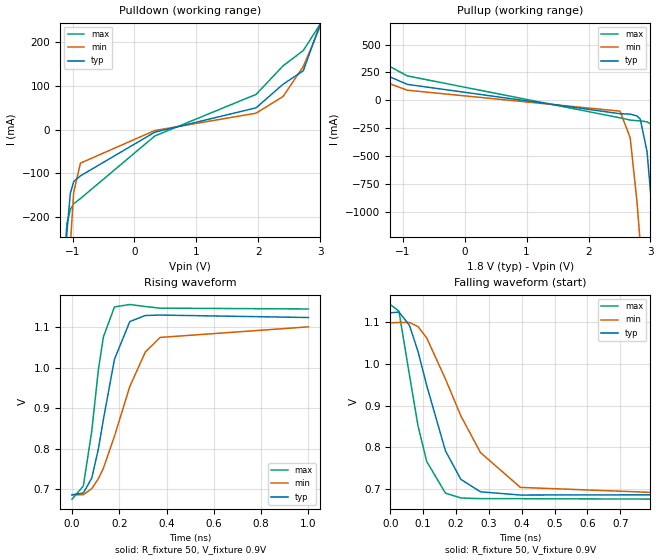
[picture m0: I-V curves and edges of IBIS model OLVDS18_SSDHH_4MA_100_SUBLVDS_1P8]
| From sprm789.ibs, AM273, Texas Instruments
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|   Model Cell OLVDS18_SSDHH_4MA_100_SUBLVDS_1P8
|OLVDS18_SSDHH_4MA_100_SUBLVDS_1P8
[Model]   OLVDS18_SSDHH_4MA_100_SUBLVDS_1P8
Model_type   Output
Polarity   Non-Inverting
Cref =  15.0001pF
Rref =  101.0000M
Vref =  0V
Vmeas =  1.08
C_comp   1.5p   1.5p   1.5p
[Temperature Range]   25   125   -40
[Voltage Range]   1.8   1.62   1.98
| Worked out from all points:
|   slope of the pulldown table from 0 to 0.27 V, typ, clamps not added: 14.5 ohm
|   slope of the pullup table from 0 to 0.27 V, typ, clamps not added: 11 ohm
|   rising waveform, R_fixture 50, V_fixture 0.9V: 20-80 % time 82.8ps typ, 145ps min, 56.8ps max; typ from 0.687 V to 1.12 V
|   falling waveform, R_fixture 50, V_fixture 0.9V: 20-80 % time 94.7ps typ, 152ps min, 65.6ps max; typ from 1.12 V to 0.686 V
| Nom Voltages:
|   BIAS1=1.2, BIAS2=1.2, VDD=1.1, VDDS=1.8, BUS_BIAS3=0, BUS_VSSS=0,
|   ESD_BIASFET=0, VSS=0
| Min Voltages:
|   BIAS1=1.2, BIAS2=1.2, VDD=0.99, VDDS=1.62, BUS_BIAS3=0, BUS_VSSS=0,
|   ESD_BIASFET=0, VSS=0
| Max Voltages:
|   BIAS1=1.2, BIAS2=1.2, VDD=1.21, VDDS=1.98, BUS_BIAS3=0, BUS_VSSS=0,
|   ESD_BIASFET=0, VSS=0
[Pulldown]
|   voltage   I(typ)   I(min)   I(max)
-1.8V     -5.997A    -6.31A     -5.865A
-1.145V   -444.7mA   -793.1mA   -323.8mA
-1.091V   -235mA     -485.1mA   -214.4mA
-1.036V   -145.6mA   -265.1mA   -182.9mA
-981.8mV  -118.4mA   -143.7mA   -169.4mA
-872.7mV  -105.5mA   -76.4mA    -157.4mA
327.3mV   -5.638mA   -1.825mA   -14.39mA
1.964V    50.15mA    37.92mA    80.87mA
2.4V      104.1mA    76.09mA    146.2mA
2.727V    135mA      144.8mA    181.3mA
3.055V    264.2mA    254.9mA    254mA
3.6V      552.6mA    862.1mA    610.6mA
[Pullup]
|   voltage   I(typ)   I(min)   I(max)
-1.8V     475.7mA    399.1mA    649.8mA
-1.309V   234.4mA    168.8mA    333.5mA
-927.3mV  142.3mA    89.88mA    218.4mA
2.509V    -121.3mA   -98.38mA   -158.3mA
2.673V    -124.8mA   -336.6mA   -178.3mA
2.782V    -141.4mA   -907.8mA   -184mA
2.836V    -170.1mA   -1.289A    -184.9mA
2.945V    -461.1mA   -2.15A     -194.8mA
3.055V    -1.17A     -3.083A    -228.3mA
3.164V    -2.06A     -4.046A    -505.6mA
3.273V    -3.022A    -5.011A    -1.263A
3.6V      -6.001A    -7.906A    -4.195A
[Ramp]
| variable   typ   min   max
dV/dt_f 0.18191049/97.259722p 0.15593189/0.14627382n 0.22158214/81.912241p
dV/dt_r 0.26008288/85.557834p 0.22969898/0.14240626n  0.2949732/60.138567p
R_load = 50
[Rising Waveform]
R_fixture = 50
V_fixture = 0.9V
V_fixture_min = 0.9V
V_fixture_max = 0.9V
|   time   V(typ)   V(min)   V(max)
0s        687mV      686.6mV    675.7mV
48.15ps   691.4mV    687.1mV    708.8mV
83.61ps   727.8mV    702.1mV    843.5mV
111.7ps   799.7mV    726.4mV    994.4mV
132.8ps   872mV      752.2mV    1.075V
179.6ps   1.02V      830.7mV    1.149V
244.6ps   1.113V     953.4mV    1.155V
310.2ps   1.128V     1.038V     1.15V
372.8ps   1.129V     1.074V     1.146V
1ns       1.123V     1.1V       1.144V
[Falling Waveform]
R_fixture = 50
V_fixture = 0.9V
V_fixture_min = 0.9V
V_fixture_max = 0.9V
|   time   V(typ)   V(min)   V(max)
0s        1.122V     1.098V     1.142V
26.23ps   1.124V     1.099V     1.126V
58.19ps   1.092V     1.099V     972.8mV
84.4ps    1.029V     1.089V     850.9mV
110.7ps   948.3mV    1.062V     766mV
167.9ps   791.3mV    963.4mV    690.1mV
214.7ps   723.1mV    875.2mV    678.6mV
274.6ps   693.3mV    787.2mV    676.9mV
396ps     685.6mV    703.9mV    676.9mV
1ns       686.4mV    685.7mV    675.3mV
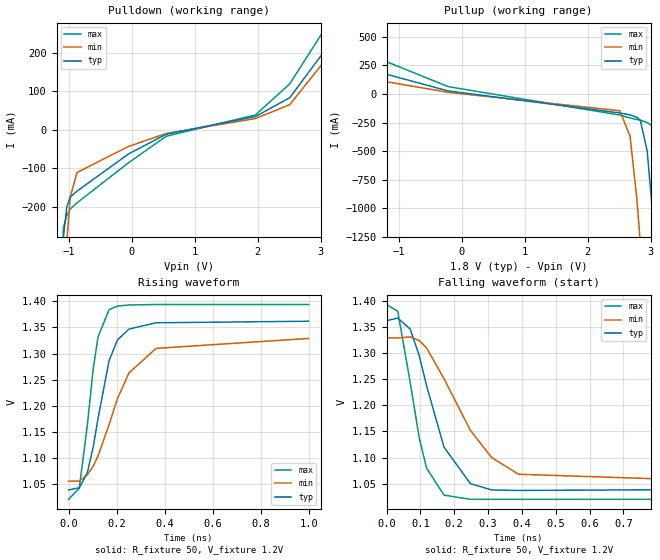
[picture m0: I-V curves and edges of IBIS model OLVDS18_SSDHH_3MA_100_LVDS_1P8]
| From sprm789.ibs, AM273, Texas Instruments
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|   Model Cell OLVDS18_SSDHH_3MA_100_LVDS_1P8
|OLVDS18_SSDHH_3MA_100_LVDS_1P8
[Model]   OLVDS18_SSDHH_3MA_100_LVDS_1P8
Model_type   Output
Polarity   Non-Inverting
Cref =  15.0001pF
Rref =  101.0000M
Vref =  0V
Vmeas =  1.08
C_comp   1.5p   1.5p   1.5p
[Temperature Range]   25   125   -40
[Voltage Range]   1.8   1.62   1.98
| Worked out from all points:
|   slope of the pulldown table from 0 to 0.27 V, typ, clamps not added: 9.82 ohm
|   slope of the pullup table from 0 to 0.27 V, typ, clamps not added: 25.2 ohm
|   rising waveform, R_fixture 50, V_fixture 1.2V: 20-80 % time 80.9ps typ, 140ps min, 54.5ps max; typ from 1.04 V to 1.36 V
|   falling waveform, R_fixture 50, V_fixture 1.2V: 20-80 % time 85.4ps typ, 143ps min, 59ps max; typ from 1.36 V to 1.04 V
| Nom Voltages:
|   BIAS1=1.2, BIAS2=1.2, VDD=1.1, VDDS=1.8, BUS_BIAS3=0, BUS_VSSS=0,
|   ESD_BIASFET=0, VSS=0
| Min Voltages:
|   BIAS1=1.2, BIAS2=1.2, VDD=0.99, VDDS=1.62, BUS_BIAS3=0, BUS_VSSS=0,
|   ESD_BIASFET=0, VSS=0
| Max Voltages:
|   BIAS1=1.2, BIAS2=1.2, VDD=1.21, VDDS=1.98, BUS_BIAS3=0, BUS_VSSS=0,
|   ESD_BIASFET=0, VSS=0
[Pulldown]
|   voltage   I(typ)   I(min)   I(max)
-1.8V     -6.003A    -6.315A    -5.869A
-1.091V   -280.6mA   -504mA     -254.8mA
-1.036V   -200.4mA   -290.6mA   -222.5mA
-981.8mV  -175.1mA   -175mA     -206.4mA
-872.7mV  -159.8mA   -111.1mA   -190.1mA
-54.55mV  -62.93mA   -43.42mA   -85.81mA
545.5mV   -11.5mA    -9.788mA   -16.87mA
1.964V    34.37mA    29.24mA    38.61mA
2.509V    83.4mA     65.25mA    119.5mA
3.164V    227.4mA    199.7mA    287.4mA
3.382V    295.2mA    298.5mA    403.3mA
3.6V      374.9mA    801.1mA    536.2mA
[Pullup]
|   voltage   I(typ)   I(min)   I(max)
-1.8V     321.7mA    319.1mA    577mA
-1.255V   180.9mA    112.4mA    294.8mA
-218.2mV  26.9mA     14.83mA    64.67mA
2.509V    -165.6mA   -146.3mA   -184.2mA
2.673V    -182.3mA   -368.3mA   -209.3mA
2.782V    -203.3mA   -924.6mA   -223.2mA
2.836V    -230.3mA   -1.302A    -228.8mA
2.945V    -496.6mA   -2.158A    -249.3mA
3.055V    -1.186A    -3.089A    -290.7mA
3.164V    -2.07A     -4.052A    -542.6mA
3.273V    -3.029A    -5.017A    -1.279A
3.6V      -6.007A    -7.911A    -4.201A
[Ramp]
| variable   typ   min   max
dV/dt_f 0.19168188/0.10159416n 0.15994001/0.15868861n 0.22678237/73.911952p
dV/dt_r 0.24315086/0.10135387n 0.19243998/0.15684725n 0.28731072/71.710216p
R_load = 50
[Rising Waveform]
R_fixture = 50
V_fixture = 1.2V
V_fixture_min = 1.2V
V_fixture_max = 1.2V
|   time   V(typ)   V(min)   V(max)
0s        1.039V     1.056V     1.021V
44.78ps   1.043V     1.056V     1.042V
78.34ps   1.072V     1.068V     1.163V
103.1ps   1.122V     1.085V     1.272V
123ps     1.176V     1.104V     1.332V
168.7ps   1.286V     1.164V     1.384V
203.3ps   1.326V     1.213V     1.391V
251.7ps   1.347V     1.263V     1.393V
365ps     1.359V     1.31V      1.394V
1ns       1.362V     1.329V     1.394V
[Falling Waveform]
R_fixture = 50
V_fixture = 1.2V
V_fixture_min = 1.2V
V_fixture_max = 1.2V
|   time   V(typ)   V(min)   V(max)
0s        1.362V     1.329V     1.393V
33.18ps   1.367V     1.329V     1.38V
69.98ps   1.346V     1.331V     1.244V
96.57ps   1.295V     1.324V     1.138V
118.2ps   1.238V     1.31V      1.08V
169.8ps   1.12V      1.251V     1.028V
248ps     1.05V      1.152V     1.02V
310.7ps   1.038V     1.1V       1.02V
390.3ps   1.037V     1.068V     1.02V
1ns       1.039V     1.055V     1.02V
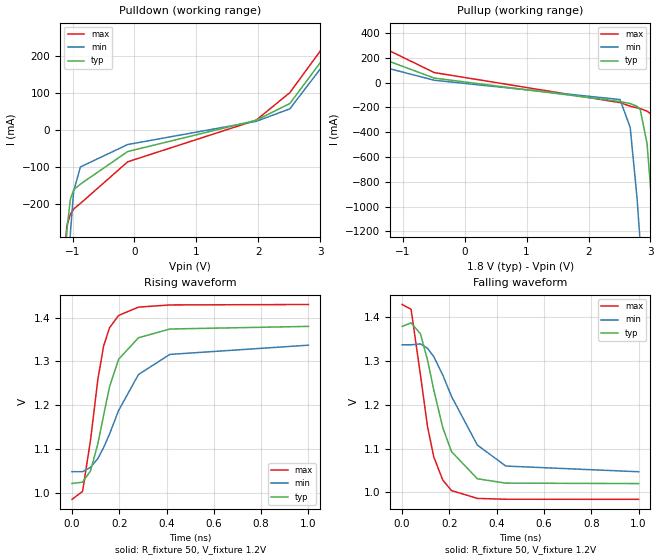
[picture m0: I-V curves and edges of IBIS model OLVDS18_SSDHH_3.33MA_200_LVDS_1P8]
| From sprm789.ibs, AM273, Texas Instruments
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|   Model Cell OLVDS18_SSDHH_3.33MA_200_LVDS_1P8
|OLVDS18_SSDHH_3.33MA_200_LVDS_1P8
[Model]   OLVDS18_SSDHH_3.33MA_200_LVDS_1P8
Model_type   Output
Polarity   Non-Inverting
Cref =  15.0001pF
Rref =  101.0000M
Vref =  0V
Vmeas =  1.08
C_comp   1.5p   1.5p   1.5p
[Temperature Range]   25   125   -40
[Voltage Range]   1.8   1.62   1.98
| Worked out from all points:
|   slope of the pulldown table from 0 to 0.27 V, typ, clamps not added: 10.7 ohm
|   slope of the pullup table from 0 to 0.27 V, typ, clamps not added: 34.5 ohm
|   rising waveform, R_fixture 50, V_fixture 1.2V: 20-80 % time 98.8ps typ, 160ps min, 68.5ps max; typ from 1.02 V to 1.38 V
|   falling waveform, R_fixture 50, V_fixture 1.2V: 20-80 % time 104ps typ, 160ps min, 76.9ps max; typ from 1.38 V to 1.02 V
| Nom Voltages:
|   BIAS1=1.2, BIAS2=1.2, VDD=1.1, VDDS=1.8, BUS_BIAS3=0, BUS_VSSS=0,
|   ESD_BIASFET=0, VSS=0
| Min Voltages:
|   BIAS1=1.2, BIAS2=1.2, VDD=0.99, VDDS=1.62, BUS_BIAS3=0, BUS_VSSS=0,
|   ESD_BIASFET=0, VSS=0
| Max Voltages:
|   BIAS1=1.2, BIAS2=1.2, VDD=1.21, VDDS=1.98, BUS_BIAS3=0, BUS_VSSS=0,
|   ESD_BIASFET=0, VSS=0
[Pulldown]
|   voltage   I(typ)   I(min)   I(max)
-1.8V     -6.002A    -6.313A    -5.869A
-1.145V   -469.1mA   -802.4mA   -357.8mA
-1.091V   -270.3mA   -497.9mA   -258.3mA
-1.036V   -188mA     -282.5mA   -228.2mA
-981.8mV  -162mA     -165.2mA   -213.7mA
-872.7mV  -146.6mA   -100.3mA   -198.7mA
-109.1mV  -58.72mA   -39.87mA   -86.43mA
1.964V    25.56mA    22.55mA    25.7mA
2.509V    70.6mA     56.36mA    100.1mA
3.273V    242.3mA    223.4mA    274.5mA
3.382V    278.4mA    290.7mA    313.4mA
3.6V      357.4mA    796.4mA    404.5mA
[Pullup]
|   voltage   I(typ)   I(min)   I(max)
-1.8V     309mA      313.3mA    437.4mA
-1.418V   209.6mA    139.6mA    307.4mA
-490.9mV  37.11mA    19.76mA    81.69mA
2.509V    -151.8mA   -135.8mA   -160.9mA
2.673V    -168.5mA   -360.8mA   -189.2mA
2.782V    -189.5mA   -920.5mA   -203.3mA
2.836V    -217.2mA   -1.299A    -209mA
2.945V    -488.9mA   -2.156A    -229.7mA
3.055V    -1.183A    -3.087A    -271.6mA
3.164V    -2.068A    -4.05A     -532mA
3.273V    -3.027A    -5.015A    -1.274A
3.6V      -6.006A    -7.91A     -4.2A
[Ramp]
| variable   typ   min   max
dV/dt_f 0.19787594/0.11739562n 0.15891786/0.16781205n 0.25058059/94.168038p
dV/dt_r 0.26663218/0.11549698n 0.19998742/0.17131782n 0.34035729/85.018329p
R_load = 50
[Rising Waveform]
R_fixture = 50
V_fixture = 1.2V
V_fixture_min = 1.2V
V_fixture_max = 1.2V
|   time   V(typ)   V(min)   V(max)
0s        1.021V     1.048V     984.8mV
44.88ps   1.024V     1.048V     1.003V
78.69ps   1.05V      1.058V     1.121V
109.5ps   1.112V     1.078V     1.259V
133.8ps   1.177V     1.103V     1.335V
158.9ps   1.242V     1.134V     1.377V
197.3ps   1.305V     1.188V     1.405V
281.3ps   1.354V     1.27V      1.424V
414ps     1.374V     1.316V     1.429V
1ns       1.38V      1.337V     1.43V
[Falling Waveform]
R_fixture = 50
V_fixture = 1.2V
V_fixture_min = 1.2V
V_fixture_max = 1.2V
|   time   V(typ)   V(min)   V(max)
0s        1.379V     1.337V     1.429V
37.76ps   1.387V     1.337V     1.418V
77.38ps   1.362V     1.339V     1.268V
107.3ps   1.302V     1.329V     1.15V
133.7ps   1.234V     1.31V      1.081V
171.6ps   1.148V     1.268V     1.028V
208.7ps   1.093V     1.219V     1.004V
317.9ps   1.031V     1.108V     986.1mV
438.2ps   1.021V     1.06V      984.2mV
1ns       1.02V      1.047V     984mV
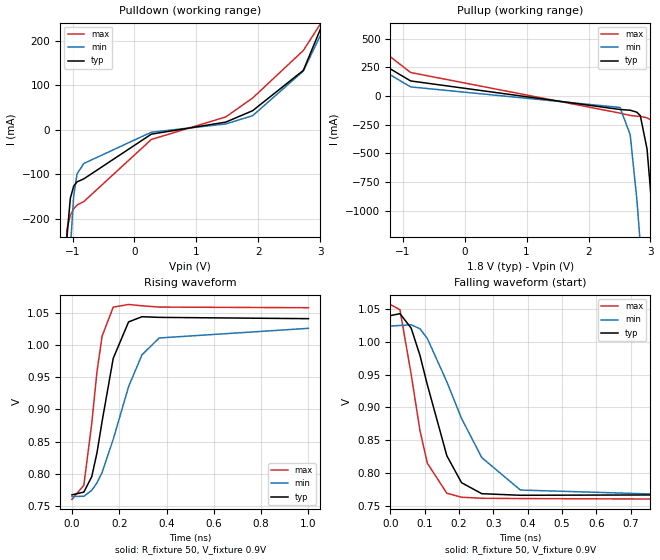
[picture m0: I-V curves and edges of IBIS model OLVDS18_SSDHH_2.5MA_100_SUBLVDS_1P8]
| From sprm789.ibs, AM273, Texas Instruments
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|   Model Cell OLVDS18_SSDHH_2.5MA_100_SUBLVDS_1P8
|OLVDS18_SSDHH_2.5MA_100_SUBLVDS_1P8
[Model]   OLVDS18_SSDHH_2.5MA_100_SUBLVDS_1P8
Model_type   Output
Polarity   Non-Inverting
Cref =  15.0001pF
Rref =  101.0000M
Vref =  0V
Vmeas =  1.08
C_comp   1.5p   1.5p   1.5p
[Temperature Range]   25   125   -40
[Voltage Range]   1.8   1.62   1.98
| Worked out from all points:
|   slope of the pulldown table from 0 to 0.27 V, typ, clamps not added: 16 ohm
|   slope of the pullup table from 0 to 0.27 V, typ, clamps not added: 13 ohm
|   rising waveform, R_fixture 50, V_fixture 0.9V: 20-80 % time 78.5ps typ, 136ps min, 53.2ps max; typ from 0.767 V to 1.04 V
|   falling waveform, R_fixture 50, V_fixture 0.9V: 20-80 % time 85.2ps typ, 137ps min, 58.3ps max; typ from 1.04 V to 0.766 V
| Nom Voltages:
|   BIAS1=1.2, BIAS2=1.2, VDD=1.1, VDDS=1.8, BUS_BIAS3=0, BUS_VSSS=0,
|   ESD_BIASFET=0, VSS=0
| Min Voltages:
|   BIAS1=1.2, BIAS2=1.2, VDD=0.99, VDDS=1.62, BUS_BIAS3=0, BUS_VSSS=0,
|   ESD_BIASFET=0, VSS=0
| Max Voltages:
|   BIAS1=1.2, BIAS2=1.2, VDD=1.21, VDDS=1.98, BUS_BIAS3=0, BUS_VSSS=0,
|   ESD_BIASFET=0, VSS=0
[Pulldown]
|   voltage   I(typ)   I(min)   I(max)
-1.8V     -5.998A    -6.311A    -5.866A
-1.091V   -242.4mA   -488.3mA   -223.9mA
-1.036V   -154.3mA   -269.5mA   -192.3mA
-981.8mV  -126.9mA   -149.1mA   -178mA
-927.3mV  -117.1mA   -99.25mA   -169.2mA
-818.2mV  -110.4mA   -75.84mA   -161.5mA
272.7mV   -9.894mA   -5.523mA   -21.84mA
1.473V    17.07mA    12.97mA    28.68mA
1.909V    42.86mA    31.63mA    71.37mA
2.727V    133.4mA    131.9mA    178.1mA
3.055V    243.6mA    227.2mA    249.1mA
3.6V      493.3mA    842.2mA    552.5mA
[Pullup]
|   voltage   I(typ)   I(min)   I(max)
-1.8V     427.9mA    374.4mA    591.9mA
-872.7mV  130.7mA    78.78mA    204.1mA
2.509V    -118mA     -100.3mA   -149.8mA
2.673V    -124.5mA   -338mA     -170.3mA
2.782V    -142.2mA   -908.5mA   -176.7mA
2.836V    -171.2mA   -1.29A     -178.4mA
2.945V    -461.9mA   -2.15A     -190.4mA
3.055V    -1.17A     -3.083A    -226.3mA
3.109V    -1.602A    -3.564A    -298.8mA
3.164V    -2.06A     -4.047A    -505.4mA
3.273V    -3.022A    -5.011A    -1.263A
3.6V      -6.001A    -7.906A    -4.195A
[Ramp]
| variable   typ   min   max
dV/dt_f  0.1007977/94.40248p  91.498081m/0.14147129n 0.12834191/97.17861p
dV/dt_r 0.13244323/84.246346p 0.10726775/0.137929n  0.16642625/56.717463p
R_load = 50
[Rising Waveform]
R_fixture = 50
V_fixture = 0.9V
V_fixture_min = 0.9V
V_fixture_max = 0.9V
|   time   V(typ)   V(min)   V(max)
0s        767.4mV    764.8mV    760.4mV
50.16ps   771.6mV    765.1mV    782.2mV
83.61ps   795.6mV    774.4mV    878.2mV
105.8ps   832.7mV    786mV      958.8mV
127.5ps   881.7mV    802.2mV    1.014V
174.5ps   979.4mV    853.6mV    1.059V
239.4ps   1.036V     935.4mV    1.063V
296.2ps   1.044V     984.9mV    1.061V
368.8ps   1.043V     1.011V     1.059V
1ns       1.041V     1.026V     1.058V
[Falling Waveform]
R_fixture = 50
V_fixture = 0.9V
V_fixture_min = 0.9V
V_fixture_max = 0.9V
|   time   V(typ)   V(min)   V(max)
0s        1.04V      1.024V     1.057V
28.04ps   1.043V     1.025V     1.049V
60.65ps   1.021V     1.026V     950.5mV
86.21ps   979.5mV    1.02V      864.9mV
107.9ps   934.3mV    1.005V     814.6mV
164.7ps   826mV      938.9mV    768.8mV
207.5ps   784.9mV    883mV      762.7mV
266.5ps   768.1mV    823.2mV    761.1mV
379ps     765.7mV    773.7mV    760.7mV
1ns       766.5mV    763.9mV    759.5mV
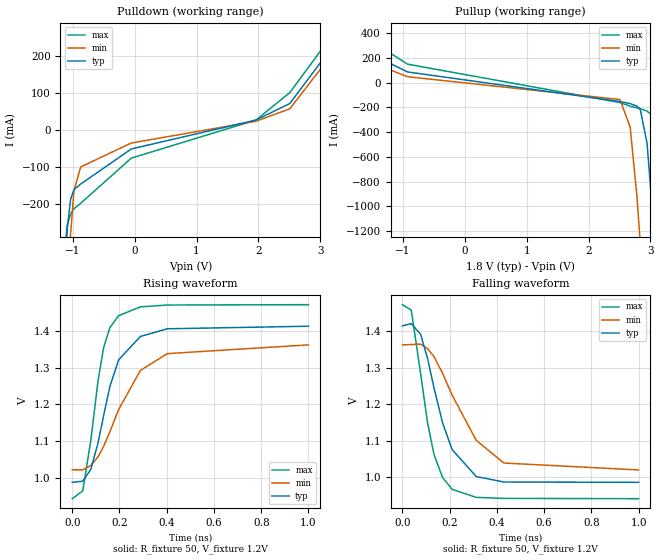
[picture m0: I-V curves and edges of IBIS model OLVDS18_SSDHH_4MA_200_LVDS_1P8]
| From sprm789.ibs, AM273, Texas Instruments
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|   Model Cell OLVDS18_SSDHH_4MA_200_LVDS_1P8
|OLVDS18_SSDHH_4MA_200_LVDS_1P8
[Model]   OLVDS18_SSDHH_4MA_200_LVDS_1P8
Model_type   Output
Polarity   Non-Inverting
Cref =  15.0001pF
Rref =  101.0000M
Vref =  0V
Vmeas =  1.08
C_comp   1.5p   1.5p   1.5p
[Temperature Range]   25   125   -40
[Voltage Range]   1.8   1.62   1.98
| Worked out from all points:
|   slope of the pulldown table from 0 to 0.27 V, typ, clamps not added: 10.4 ohm
|   slope of the pullup table from 0 to 0.27 V, typ, clamps not added: 30.6 ohm
|   rising waveform, R_fixture 50, V_fixture 1.2V: 20-80 % time 99.5ps typ, 155ps min, 69ps max; typ from 0.987 V to 1.41 V
|   falling waveform, R_fixture 50, V_fixture 1.2V: 20-80 % time 108ps typ, 166ps min, 79.6ps max; typ from 1.41 V to 0.986 V
| Nom Voltages:
|   BIAS1=1.2, BIAS2=1.2, VDD=1.1, VDDS=1.8, BUS_BIAS3=0, BUS_VSSS=0,
|   ESD_BIASFET=0, VSS=0
| Min Voltages:
|   BIAS1=1.2, BIAS2=1.2, VDD=0.99, VDDS=1.62, BUS_BIAS3=0, BUS_VSSS=0,
|   ESD_BIASFET=0, VSS=0
| Max Voltages:
|   BIAS1=1.2, BIAS2=1.2, VDD=1.21, VDDS=1.98, BUS_BIAS3=0, BUS_VSSS=0,
|   ESD_BIASFET=0, VSS=0
[Pulldown]
|   voltage   I(typ)   I(min)   I(max)
-1.8V     -6.002A    -6.313A    -5.869A
-1.145V   -469.2mA   -802.4mA   -358.1mA
-1.091V   -270.5mA   -498mA     -258.7mA
-1.036V   -188.3mA   -282.6mA   -228.6mA
-981.8mV  -162.4mA   -165.4mA   -214.2mA
-872.7mV  -147.1mA   -100.6mA   -199.3mA
-54.55mV  -51.85mA   -35.77mA   -76.77mA
1.964V    26.68mA    23.43mA    26.84mA
2.509V    71.64mA    57.21mA    101.3mA
3.273V    242.7mA    223.5mA    275.5mA
3.382V    278.8mA    290.7mA    314.4mA
3.6V      357.6mA    796.2mA    405.4mA
[Pullup]
|   voltage   I(typ)   I(min)   I(max)
-1.8V     306.5mA    311.8mA    434.7mA
-1.582V   248.4mA    176.8mA    360.7mA
-927.3mV  87.71mA    48.97mA    150.6mA
2.509V    -151.7mA   -135.7mA   -160.7mA
2.673V    -168.4mA   -360.7mA   -189.1mA
2.782V    -189.4mA   -920.4mA   -203.2mA
2.836V    -217.1mA   -1.299A    -209mA
2.945V    -488.8mA   -2.156A    -229.6mA
3.055V    -1.183A    -3.087A    -271.6mA
3.164V    -2.068A    -4.05A     -532mA
3.273V    -3.027A    -5.015A    -1.274A
3.6V      -6.006A    -7.91A     -4.2A
[Ramp]
| variable   typ   min   max
dV/dt_f 0.23525211/0.12064186n 0.18932691/0.17314391n 0.29708818/96.099177p
dV/dt_r 0.30711866/0.1083655n  0.2305142/0.16020396n 0.39283537/80.525444p
R_load = 50
[Rising Waveform]
R_fixture = 50
V_fixture = 1.2V
V_fixture_min = 1.2V
V_fixture_max = 1.2V
|   time   V(typ)   V(min)   V(max)
0s        986.9mV    1.021V     942.1mV
44.53ps   990mV      1.021V     963.5mV
78.34ps   1.022V     1.033V     1.101V
109.4ps   1.095V     1.057V     1.266V
132.7ps   1.169V     1.085V     1.355V
159.2ps   1.249V     1.125V     1.41V
196.4ps   1.322V     1.186V     1.443V
288.4ps   1.386V     1.293V     1.467V
402.3ps   1.407V     1.339V     1.472V
1ns       1.414V     1.363V     1.473V
[Falling Waveform]
R_fixture = 50
V_fixture = 1.2V
V_fixture_min = 1.2V
V_fixture_max = 1.2V
|   time   V(typ)   V(min)   V(max)
0s        1.414V     1.362V     1.472V
37.48ps   1.42V      1.363V     1.457V
77.02ps   1.391V     1.364V     1.283V
106.3ps   1.325V     1.352V     1.149V
133.4ps   1.245V     1.33V      1.063V
169.4ps   1.15V      1.285V     1V
210.1ps   1.076V     1.225V     967.1mV
312.4ps   1.002V     1.101V     945.1mV
429.6ps   987.1mV    1.039V     942.3mV
1ns       986.2mV    1.02V      941.5mV
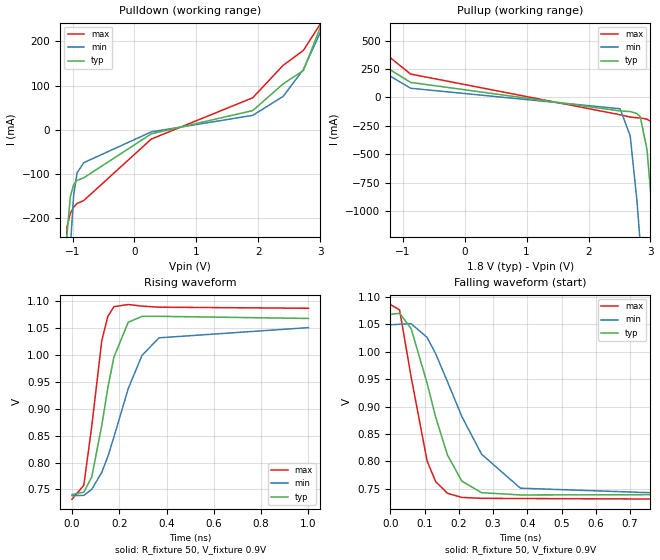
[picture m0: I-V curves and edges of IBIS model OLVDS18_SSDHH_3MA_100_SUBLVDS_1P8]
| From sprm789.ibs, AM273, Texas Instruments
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|   Model Cell OLVDS18_SSDHH_3MA_100_SUBLVDS_1P8
|OLVDS18_SSDHH_3MA_100_SUBLVDS_1P8
[Model]   OLVDS18_SSDHH_3MA_100_SUBLVDS_1P8
Model_type   Output
Polarity   Non-Inverting
Cref =  15.0001pF
Rref =  101.0000M
Vref =  0V
Vmeas =  1.08
C_comp   1.5p   1.5p   1.5p
[Temperature Range]   25   125   -40
[Voltage Range]   1.8   1.62   1.98
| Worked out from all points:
|   slope of the pulldown table from 0 to 0.27 V, typ, clamps not added: 15.4 ohm
|   slope of the pullup table from 0 to 0.27 V, typ, clamps not added: 12.3 ohm
|   rising waveform, R_fixture 50, V_fixture 0.9V: 20-80 % time 79.9ps typ, 139ps min, 54.3ps max; typ from 0.74 V to 1.07 V
|   falling waveform, R_fixture 50, V_fixture 0.9V: 20-80 % time 88.3ps typ, 142ps min, 60.9ps max; typ from 1.07 V to 0.74 V
| Nom Voltages:
|   BIAS1=1.2, BIAS2=1.2, VDD=1.1, VDDS=1.8, BUS_BIAS3=0, BUS_VSSS=0,
|   ESD_BIASFET=0, VSS=0
| Min Voltages:
|   BIAS1=1.2, BIAS2=1.2, VDD=0.99, VDDS=1.62, BUS_BIAS3=0, BUS_VSSS=0,
|   ESD_BIASFET=0, VSS=0
| Max Voltages:
|   BIAS1=1.2, BIAS2=1.2, VDD=1.21, VDDS=1.98, BUS_BIAS3=0, BUS_VSSS=0,
|   ESD_BIASFET=0, VSS=0
[Pulldown]
|   voltage   I(typ)   I(min)   I(max)
-1.8V     -5.998A    -6.311A    -5.866A
-1.091V   -240mA     -487.3mA   -220.7mA
-1.036V   -151.4mA   -268.1mA   -189.1mA
-981.8mV  -124mA     -147.3mA   -175.2mA
-927.3mV  -114.5mA   -97.37mA   -166.7mA
-818.2mV  -108.6mA   -74.45mA   -160mA
272.7mV   -9.224mA   -4.806mA   -20.96mA
1.909V    43.28mA    32.47mA    72.21mA
2.4V      103.5mA    75.31mA    145.5mA
2.727V    134mA      136.2mA    179.2mA
3.055V    250.5mA    236.4mA    250.7mA
3.6V      513.2mA    848.8mA    572mA
[Pullup]
|   voltage   I(typ)   I(min)   I(max)
-1.8V     444mA      382.6mA    611.4mA
-872.7mV  132.1mA    80.56mA    205.6mA
2.509V    -119.1mA   -99.69mA   -152.7mA
2.673V    -124.6mA   -337.5mA   -173mA
2.782V    -141.9mA   -908.3mA   -179.1mA
2.836V    -170.8mA   -1.29A     -180.6mA
2.945V    -461.6mA   -2.15A     -191.9mA
3.055V    -1.17A     -3.083A    -226.9mA
3.109V    -1.602A    -3.564A    -299mA
3.164V    -2.06A     -4.047A    -505.5mA
3.273V    -3.022A    -5.011A    -1.263A
3.6V      -6.001A    -7.906A    -4.195A
[Ramp]
| variable   typ   min   max
dV/dt_f 0.12581364/94.968355p 0.10863678/0.143361n  0.16005686/89.185332p
dV/dt_r  0.1755703/82.883223p 0.14803455/0.13503722n  0.2105199/57.770565p
R_load = 50
[Rising Waveform]
R_fixture = 50
V_fixture = 0.9V
V_fixture_min = 0.9V
V_fixture_max = 0.9V
|   time   V(typ)   V(min)   V(max)
0s        740.4mV    738.4mV    731.6mV
50.15ps   745mV      739mV      758mV
83.62ps   773.2mV    750.2mV    867.4mV
126.1ps   869.3mV    781.8mV    1.027V
151.7ps   939mV      811.3mV    1.072V
177.6ps   996.4mV    847.9mV    1.09V
238.1ps   1.061V     937.8mV    1.094V
296.4ps   1.072V     999.5mV    1.091V
368.1ps   1.072V     1.032V     1.089V
1ns       1.068V     1.051V     1.087V
[Falling Waveform]
R_fixture = 50
V_fixture = 0.9V
V_fixture_min = 0.9V
V_fixture_max = 0.9V
|   time   V(typ)   V(min)   V(max)
0s        1.068V     1.049V     1.086V
27.13ps   1.07V      1.05V      1.076V
60.64ps   1.042V     1.051V     954.1mV
107.2ps   942.9mV    1.026V     801.1mV
132.3ps   880.7mV    996.2mV    763.1mV
166.9ps   811.3mV    945.1mV    741.7mV
208.8ps   764mV      881.6mV    734.3mV
266.4ps   742.9mV    813mV      732.6mV
379.6ps   738.8mV    751.1mV    732.3mV
1ns       739.6mV    737.6mV    730.8mV
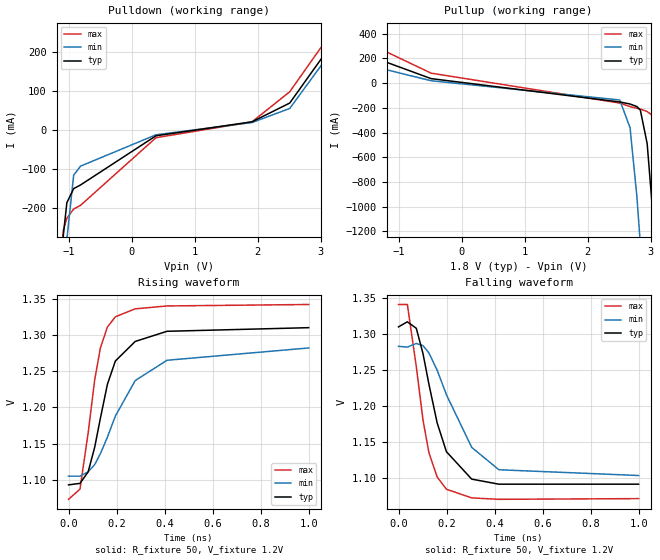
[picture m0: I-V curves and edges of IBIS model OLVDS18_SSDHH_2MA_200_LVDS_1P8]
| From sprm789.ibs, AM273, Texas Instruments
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|   Model Cell OLVDS18_SSDHH_2MA_200_LVDS_1P8
|OLVDS18_SSDHH_2MA_200_LVDS_1P8
[Model]   OLVDS18_SSDHH_2MA_200_LVDS_1P8
Model_type   Output
Polarity   Non-Inverting
Cref =  15.0001pF
Rref =  101.0000M
Vref =  0V
Vmeas =  1.08
C_comp   1.5p   1.5p   1.5p
[Temperature Range]   25   125   -40
[Voltage Range]   1.8   1.62   1.98
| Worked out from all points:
|   slope of the pulldown table from 0 to 0.27 V, typ, clamps not added: 11.2 ohm
|   slope of the pullup table from 0 to 0.27 V, typ, clamps not added: 40.7 ohm
|   rising waveform, R_fixture 50, V_fixture 1.2V: 20-80 % time 96.6ps typ, 171ps min, 68.9ps max; typ from 1.09 V to 1.31 V
|   falling waveform, R_fixture 50, V_fixture 1.2V: 20-80 % time 96.1ps typ, 147ps min, 71.7ps max; typ from 1.31 V to 1.09 V
| Nom Voltages:
|   BIAS1=1.2, BIAS2=1.2, VDD=1.1, VDDS=1.8, BUS_BIAS3=0, BUS_VSSS=0,
|   ESD_BIASFET=0, VSS=0
| Min Voltages:
|   BIAS1=1.2, BIAS2=1.2, VDD=0.99, VDDS=1.62, BUS_BIAS3=0, BUS_VSSS=0,
|   ESD_BIASFET=0, VSS=0
| Max Voltages:
|   BIAS1=1.2, BIAS2=1.2, VDD=1.21, VDDS=1.98, BUS_BIAS3=0, BUS_VSSS=0,
|   ESD_BIASFET=0, VSS=0
[Pulldown]
|   voltage   I(typ)   I(min)   I(max)
-1.8V     -6.002A    -6.313A    -5.869A
-1.145V   -468.8mA   -802.3mA   -357.3mA
-1.091V   -269.8mA   -497.7mA   -257.5mA
-1.036V   -187.4mA   -282.3mA   -227.3mA
-927.3mV  -151.2mA   -116.5mA   -203.5mA
-818.2mV  -141.8mA   -93.48mA   -194.1mA
381.8mV   -15.52mA   -12.94mA   -20.43mA
1.909V    20.33mA    18.48mA    20.24mA
2.509V    68.55mA    54.68mA    97.59mA
3.273V    241.5mA    223.4mA    272.5mA
3.382V    277.6mA    290.8mA    311.4mA
3.6V      357.1mA    796.6mA    402.7mA
[Pullup]
|   voltage   I(typ)   I(min)   I(max)
-1.8V     313.9mA    316.4mA    442.7mA
-1.364V   199.9mA    129.4mA    293mA
-490.9mV  36.74mA    19.68mA    81.14mA
2.509V    -152mA     -136mA     -161.2mA
2.673V    -168.7mA   -360.9mA   -189.4mA
2.782V    -189.7mA   -920.5mA   -203.4mA
2.836V    -217.3mA   -1.299A    -209.2mA
2.945V    -489mA     -2.156A    -229.8mA
3.055V    -1.183A    -3.087A    -271.7mA
3.164V    -2.068A    -4.05A     -532.1mA
3.273V    -3.027A    -5.015A    -1.274A
3.6V      -6.006A    -7.91A     -4.2A
[Ramp]
| variable   typ   min   max
dV/dt_f 0.12287329/0.11076498n 97.910554m/0.15745962n 0.15538958/89.55526p
dV/dt_r 0.17240035/0.1340443n 0.12953244/0.20236961n 0.21799807/95.926415p
R_load = 50
[Rising Waveform]
R_fixture = 50
V_fixture = 1.2V
V_fixture_min = 1.2V
V_fixture_max = 1.2V
|   time   V(typ)   V(min)   V(max)
0s        1.093V     1.105V     1.073V
47.64ps   1.095V     1.105V     1.087V
81.83ps   1.111V     1.111V     1.165V
109ps     1.145V     1.121V     1.238V
132.7ps   1.185V     1.136V     1.282V
162.1ps   1.232V     1.159V     1.311V
195.1ps   1.264V     1.188V     1.325V
277.8ps   1.291V     1.237V     1.336V
410.1ps   1.305V     1.265V     1.34V
1ns       1.31V      1.282V     1.342V
[Falling Waveform]
R_fixture = 50
V_fixture = 1.2V
V_fixture_min = 1.2V
V_fixture_max = 1.2V
|   time   V(typ)   V(min)   V(max)
0s        1.31V      1.283V     1.341V
36.79ps   1.317V     1.282V     1.341V
74.01ps   1.308V     1.287V     1.255V
101.9ps   1.273V     1.284V     1.181V
126.3ps   1.231V     1.274V     1.136V
160.8ps   1.177V     1.25V      1.102V
199.5ps   1.137V     1.216V     1.085V
304.7ps   1.099V     1.143V     1.073V
418ps     1.092V     1.112V     1.071V
1ns       1.092V     1.104V     1.072V
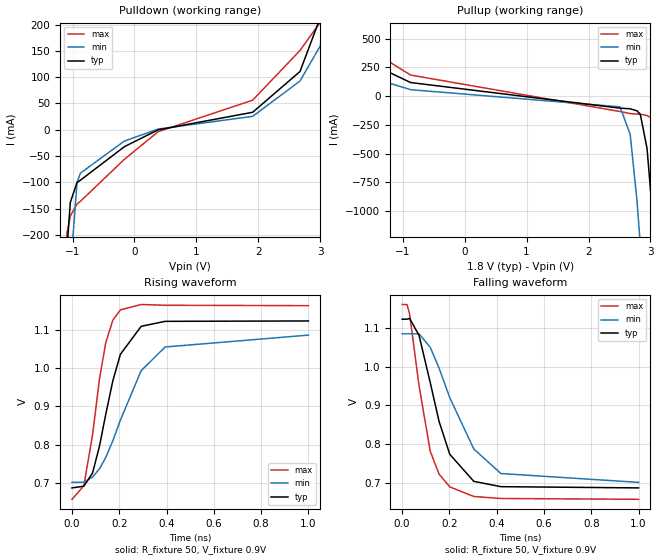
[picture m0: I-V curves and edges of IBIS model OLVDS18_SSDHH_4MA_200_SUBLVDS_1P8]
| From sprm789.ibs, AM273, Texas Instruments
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|   Model Cell OLVDS18_SSDHH_4MA_200_SUBLVDS_1P8
|OLVDS18_SSDHH_4MA_200_SUBLVDS_1P8
[Model]   OLVDS18_SSDHH_4MA_200_SUBLVDS_1P8
Model_type   Output
Polarity   Non-Inverting
Cref =  15.0001pF
Rref =  101.0000M
Vref =  0V
Vmeas =  1.08
C_comp   1.5p   1.5p   1.5p
[Temperature Range]   25   125   -40
[Voltage Range]   1.8   1.62   1.98
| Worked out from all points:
|   slope of the pulldown table from 0 to 0.27 V, typ, clamps not added: 18.2 ohm
|   slope of the pullup table from 0 to 0.27 V, typ, clamps not added: 14.1 ohm
|   rising waveform, R_fixture 50, V_fixture 0.9V: 20-80 % time 96.3ps typ, 157ps min, 68.8ps max; typ from 0.687 V to 1.12 V
|   falling waveform, R_fixture 50, V_fixture 0.9V: 20-80 % time 110ps typ, 165ps min, 81.2ps max; typ from 1.12 V to 0.686 V
| Nom Voltages:
|   BIAS1=1.2, BIAS2=1.2, VDD=1.1, VDDS=1.8, BUS_BIAS3=0, BUS_VSSS=0,
|   ESD_BIASFET=0, VSS=0
| Min Voltages:
|   BIAS1=1.2, BIAS2=1.2, VDD=0.99, VDDS=1.62, BUS_BIAS3=0, BUS_VSSS=0,
|   ESD_BIASFET=0, VSS=0
| Max Voltages:
|   BIAS1=1.2, BIAS2=1.2, VDD=1.21, VDDS=1.98, BUS_BIAS3=0, BUS_VSSS=0,
|   ESD_BIASFET=0, VSS=0
[Pulldown]
|   voltage   I(typ)   I(min)   I(max)
-1.8V     -5.997A    -6.311A    -5.864A
-1.091V   -229.3mA   -488.8mA   -197.5mA
-1.036V   -138.2mA   -270.3mA   -164.2mA
-927.3mV  -100.4mA   -100.3mA   -141.2mA
-872.7mV  -96mA      -82.63mA   -136.2mA
-163.6mV  -32.28mA   -21.52mA   -56.34mA
381.8mV   -178.6uA   1.192mA    -3.738mA
1.909V    33.21mA    25.53mA    56.26mA
2.673V    110.8mA    92.65mA    150.8mA
3V        213.2mA    159.5mA    204.6mA
3.109V    260.1mA    241.4mA    255mA
3.6V      499.8mA    845.9mA    552.3mA
[Pullup]
|   voltage   I(typ)   I(min)   I(max)
-1.8V     430.6mA    378.4mA    592.3mA
-1.418V   257.7mA    145.5mA    364.2mA
-872.7mV  117.8mA    55.8mA     183mA
2.509V    -105.1mA   -93.42mA   -134.5mA
2.673V    -110.4mA   -333.4mA   -151.8mA
2.782V    -128mA     -906mA     -156.7mA
2.836V    -157.6mA   -1.288A    -157.8mA
2.945V    -454.3mA   -2.149A    -168.8mA
3.055V    -1.167A    -3.082A    -204.6mA
3.164V    -2.058A    -4.046A    -493.9mA
3.273V    -3.02A     -5.011A    -1.258A
3.6V      -6A        -7.905A    -4.194A
[Ramp]
| variable   typ   min   max
dV/dt_f 0.15761008/0.11697951n 0.12753885/0.15572171n  0.2104113/0.11555797n
dV/dt_r 0.24340585/94.306604p 0.19097736/0.14450776n 0.30851105/71.426862p
R_load = 50
[Rising Waveform]
R_fixture = 50
V_fixture = 0.9V
V_fixture_min = 0.9V
V_fixture_max = 0.9V
|   time   V(typ)   V(min)   V(max)
0s        686.7mV    701.1mV    656.9mV
50.18ps   691.2mV    701.8mV    692.3mV
87.05ps   725.7mV    714.9mV    825.6mV
116.5ps   796.3mV    736.8mV    972.2mV
142.8ps   878.8mV    766.1mV    1.066V
172.7ps   966.4mV    809.9mV    1.125V
204.9ps   1.036V     864.3mV    1.152V
292.7ps   1.109V     993.2mV    1.166V
394.1ps   1.122V     1.055V     1.164V
1ns       1.123V     1.086V     1.163V
[Falling Waveform]
R_fixture = 50
V_fixture = 0.9V
V_fixture_min = 0.9V
V_fixture_max = 0.9V
|   time   V(typ)   V(min)   V(max)
0s        1.123V     1.085V     1.161V
20.29ps   1.123V     1.085V     1.161V
31.3ps    1.125V     1.085V     1.137V
71.48ps   1.081V     1.085V     950.2mV
118.9ps   958.3mV    1.05V      780.7mV
155.9ps   858.6mV    996.4mV    722mV
201.3ps   773.1mV    919.8mV    688.7mV
302.9ps   703.1mV    786.9mV    663.9mV
417.6ps   689.3mV    723.3mV    658.7mV
1ns       686.1mV    700.4mV    656.5mV
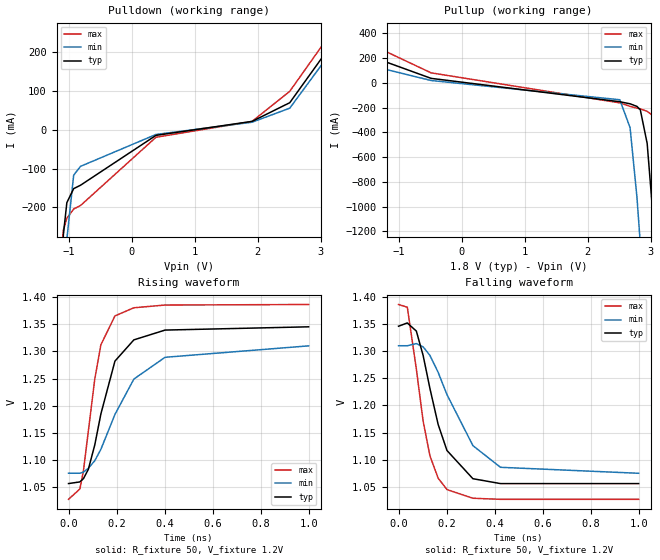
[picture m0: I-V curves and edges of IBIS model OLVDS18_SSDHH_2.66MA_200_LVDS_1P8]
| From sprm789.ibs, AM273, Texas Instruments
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|   Model Cell OLVDS18_SSDHH_2.66MA_200_LVDS_1P8
|OLVDS18_SSDHH_2.66MA_200_LVDS_1P8
[Model]   OLVDS18_SSDHH_2.66MA_200_LVDS_1P8
Model_type   Output
Polarity   Non-Inverting
Cref =  15.0001pF
Rref =  101.0000M
Vref =  0V
Vmeas =  1.08
C_comp   1.5p   1.5p   1.5p
[Temperature Range]   25   125   -40
[Voltage Range]   1.8   1.62   1.98
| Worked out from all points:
|   slope of the pulldown table from 0 to 0.27 V, typ, clamps not added: 10.9 ohm
|   slope of the pullup table from 0 to 0.27 V, typ, clamps not added: 37.8 ohm
|   rising waveform, R_fixture 50, V_fixture 1.2V: 20-80 % time 97.6ps typ, 166ps min, 68.4ps max; typ from 1.06 V to 1.34 V
|   falling waveform, R_fixture 50, V_fixture 1.2V: 20-80 % time 100ps typ, 153ps min, 74.3ps max; typ from 1.35 V to 1.06 V
| Nom Voltages:
|   BIAS1=1.2, BIAS2=1.2, VDD=1.1, VDDS=1.8, BUS_BIAS3=0, BUS_VSSS=0,
|   ESD_BIASFET=0, VSS=0
| Min Voltages:
|   BIAS1=1.2, BIAS2=1.2, VDD=0.99, VDDS=1.62, BUS_BIAS3=0, BUS_VSSS=0,
|   ESD_BIASFET=0, VSS=0
| Max Voltages:
|   BIAS1=1.2, BIAS2=1.2, VDD=1.21, VDDS=1.98, BUS_BIAS3=0, BUS_VSSS=0,
|   ESD_BIASFET=0, VSS=0
[Pulldown]
|   voltage   I(typ)   I(min)   I(max)
-1.8V     -6.002A    -6.313A    -5.869A
-1.145V   -468.9mA   -802.3mA   -357.6mA
-1.091V   -270mA     -497.8mA   -257.9mA
-1.036V   -187.7mA   -282.4mA   -227.8mA
-927.3mV  -151.6mA   -116.8mA   -204mA
-818.2mV  -142.8mA   -94.22mA   -195mA
381.8mV   -14.49mA   -12.11mA   -19.4mA
1.909V    21.45mA    19.35mA    21.45mA
2.509V    69.57mA    55.52mA    98.84mA
3.273V    241.9mA    223.4mA    273.5mA
3.382V    278mA      290.8mA    312.4mA
3.6V      357.3mA    796.5mA    403.6mA
[Pullup]
|   voltage   I(typ)   I(min)   I(max)
-1.8V     311.5mA    314.9mA    440mA
-1.364V   198mA      128.4mA    290.8mA
-490.9mV  36.92mA    19.72mA    81.42mA
2.509V    -151.9mA   -135.9mA   -161mA
2.673V    -168.6mA   -360.9mA   -189.3mA
2.782V    -189.6mA   -920.5mA   -203.4mA
2.836V    -217.3mA   -1.299A    -209.1mA
2.945V    -488.9mA   -2.156A    -229.7mA
3.055V    -1.183A    -3.087A    -271.7mA
3.164V    -2.068A    -4.05A     -532.1mA
3.273V    -3.027A    -5.015A    -1.274A
3.6V      -6.006A    -7.91A     -4.2A
[Ramp]
| variable   typ   min   max
dV/dt_f 0.16037361/0.11406359n 0.12843086/0.1626955n 0.20336833/92.056452p
dV/dt_r 0.22184256/0.12382649n 0.16643856/0.18531683n  0.2819871/90.118096p
R_load = 50
[Rising Waveform]
R_fixture = 50
V_fixture = 1.2V
V_fixture_min = 1.2V
V_fixture_max = 1.2V
|   time   V(typ)   V(min)   V(max)
0s        1.057V     1.076V     1.028V
47.28ps   1.06V      1.076V     1.047V
62.05ps   1.066V     1.078V     1.08V
82.42ps   1.083V     1.085V     1.153V
109.3ps   1.128V     1.099V     1.249V
134.8ps   1.185V     1.12V      1.312V
193.3ps   1.282V     1.184V     1.365V
272.1ps   1.321V     1.249V     1.38V
402.1ps   1.339V     1.289V     1.385V
1ns       1.345V     1.31V      1.386V
[Falling Waveform]
R_fixture = 50
V_fixture = 1.2V
V_fixture_min = 1.2V
V_fixture_max = 1.2V
|   time   V(typ)   V(min)   V(max)
0s        1.346V     1.31V      1.386V
36.56ps   1.352V     1.31V      1.381V
74.22ps   1.337V     1.314V     1.267V
102.5ps   1.292V     1.308V     1.171V
130.9ps   1.231V     1.292V     1.107V
165ps     1.165V     1.261V     1.066V
201.7ps   1.117V     1.22V      1.045V
309.7ps   1.065V     1.126V     1.029V
424.7ps   1.056V     1.086V     1.027V
1ns       1.056V     1.075V     1.027V
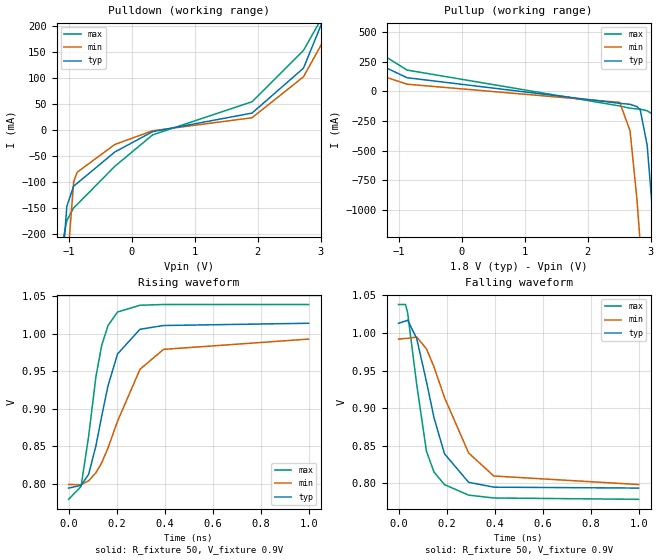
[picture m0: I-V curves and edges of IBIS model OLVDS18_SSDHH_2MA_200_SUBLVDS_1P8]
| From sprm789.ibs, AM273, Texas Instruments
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|   Model Cell OLVDS18_SSDHH_2MA_200_SUBLVDS_1P8
|OLVDS18_SSDHH_2MA_200_SUBLVDS_1P8
[Model]   OLVDS18_SSDHH_2MA_200_SUBLVDS_1P8
Model_type   Output
Polarity   Non-Inverting
Cref =  15.0001pF
Rref =  101.0000M
Vref =  0V
Vmeas =  1.08
C_comp   1.5p   1.5p   1.5p
[Temperature Range]   25   125   -40
[Voltage Range]   1.8   1.62   1.98
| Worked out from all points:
|   slope of the pulldown table from 0 to 0.27 V, typ, clamps not added: 20.5 ohm
|   slope of the pullup table from 0 to 0.27 V, typ, clamps not added: 17.6 ohm
|   rising waveform, R_fixture 50, V_fixture 0.9V: 20-80 % time 94.2ps typ, 149ps min, 68.3ps max; typ from 0.794 V to 1.01 V
|   falling waveform, R_fixture 50, V_fixture 0.9V: 20-80 % time 99.4ps typ, 149ps min, 70.7ps max; typ from 1.01 V to 0.793 V
| Nom Voltages:
|   BIAS1=1.2, BIAS2=1.2, VDD=1.1, VDDS=1.8, BUS_BIAS3=0, BUS_VSSS=0,
|   ESD_BIASFET=0, VSS=0
| Min Voltages:
|   BIAS1=1.2, BIAS2=1.2, VDD=0.99, VDDS=1.62, BUS_BIAS3=0, BUS_VSSS=0,
|   ESD_BIASFET=0, VSS=0
| Max Voltages:
|   BIAS1=1.2, BIAS2=1.2, VDD=1.21, VDDS=1.98, BUS_BIAS3=0, BUS_VSSS=0,
|   ESD_BIASFET=0, VSS=0
[Pulldown]
|   voltage   I(typ)   I(min)   I(max)
-1.8V     -5.998A    -6.311A    -5.865A
-1.091V   -236.7mA   -488.7mA   -207.7mA
-1.036V   -146.8mA   -270.1mA   -174.4mA
-927.3mV  -108.2mA   -99.81mA   -149.8mA
-872.7mV  -102.9mA   -81.68mA   -143.6mA
-272.7mV  -42.7mA    -28.28mA   -70.18mA
327.3mV   -3.733mA   -1.935mA   -9.903mA
1.909V    31.97mA    23mA       53.73mA
2.727V    118.2mA    101.6mA    152.2mA
3.055V    215.4mA    173.2mA    222.4mA
3.164V    255.2mA    233.4mA    270mA
3.6V      439.2mA    825.4mA    491.2mA
[Pullup]
|   voltage   I(typ)   I(min)   I(max)
-1.8V     381.4mA    352.5mA    530.4mA
-1.473V   262.8mA    164.1mA    375.5mA
-872.7mV  113.7mA    59.23mA    177.9mA
2.509V    -101.8mA   -93.77mA   -123.9mA
2.673V    -110.1mA   -333.6mA   -142.7mA
2.782V    -128.8mA   -906.2mA   -148.8mA
2.836V    -158.7mA   -1.288A    -150.8mA
2.945V    -455mA     -2.149A    -164.1mA
3.055V    -1.167A    -3.082A    -202.4mA
3.164V    -2.059A    -4.046A    -493.8mA
3.273V    -3.02A     -5.011A    -1.258A
3.6V      -6A        -7.905A    -4.194A
[Ramp]
| variable   typ   min   max
dV/dt_f 78.734536m/0.10948297n 66.904268m/0.15173544n 96.470151m/0.16382336n
dV/dt_r   73.0675m/0.12287388n  64.76861m/0.14727657n 0.11618292/72.196762p
R_load = 50
[Rising Waveform]
R_fixture = 50
V_fixture = 0.9V
V_fixture_min = 0.9V
V_fixture_max = 0.9V
|   time   V(typ)   V(min)   V(max)
0s        794.4mV    799.2mV    779.4mV
52.16ps   798mV      798.9mV    796.5mV
83.59ps   812.6mV    804.1mV    863.1mV
114.1ps   850.6mV    814.8mV    942.8mV
138.1ps   890.3mV    828mV      984.5mV
164.5ps   930.7mV    847.9mV    1.011V
204.2ps   973.1mV    883.6mV    1.029V
297.7ps   1.006V     952.7mV    1.038V
395.6ps   1.011V     979.2mV    1.039V
1ns       1.014V     992.9mV    1.039V
[Falling Waveform]
R_fixture = 50
V_fixture = 0.9V
V_fixture_min = 0.9V
V_fixture_max = 0.9V
|   time   V(typ)   V(min)   V(max)
0s        1.013V     991.9mV    1.038V
29.13ps   1.016V     992.8mV    1.038V
37.89ps   1.017V     992.8mV    1.027V
75.55ps   992.8mV    994.7mV    931.8mV
116.1ps   935.6mV    979mV      842.7mV
147.6ps   887.3mV    955mV      814.8mV
191.4ps   839.1mV    914mV      798mV
291.9ps   801.1mV    840.2mV    784mV
396.7ps   794.6mV    809.5mV    780.2mV
1ns       793.4mV    798.1mV    778.4mV
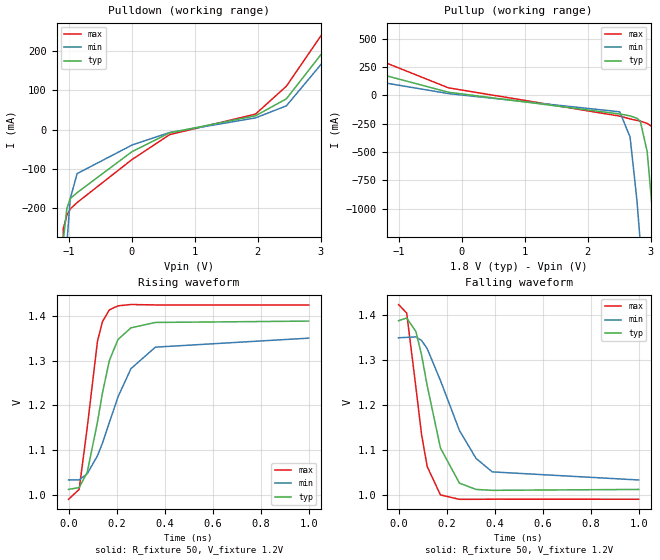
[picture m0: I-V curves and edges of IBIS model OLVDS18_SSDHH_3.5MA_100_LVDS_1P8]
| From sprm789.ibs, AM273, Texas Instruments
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|   Model Cell OLVDS18_SSDHH_3.5MA_100_LVDS_1P8
|OLVDS18_SSDHH_3.5MA_100_LVDS_1P8
[Model]   OLVDS18_SSDHH_3.5MA_100_LVDS_1P8
Model_type   Output
Polarity   Non-Inverting
Cref =  15.0001pF
Rref =  101.0000M
Vref =  0V
Vmeas =  1.08
C_comp   1.5p   1.5p   1.5p
[Temperature Range]   25   125   -40
[Voltage Range]   1.8   1.62   1.98
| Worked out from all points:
|   slope of the pulldown table from 0 to 0.27 V, typ, clamps not added: 9.61 ohm
|   slope of the pullup table from 0 to 0.27 V, typ, clamps not added: 23.4 ohm
|   rising waveform, R_fixture 50, V_fixture 1.2V: 20-80 % time 82.5ps typ, 138ps min, 55.5ps max; typ from 1.01 V to 1.39 V
|   falling waveform, R_fixture 50, V_fixture 1.2V: 20-80 % time 89.3ps typ, 148ps min, 61.5ps max; typ from 1.39 V to 1.01 V
| Nom Voltages:
|   BIAS1=1.2, BIAS2=1.2, VDD=1.1, VDDS=1.8, BUS_BIAS3=0, BUS_VSSS=0,
|   ESD_BIASFET=0, VSS=0
| Min Voltages:
|   BIAS1=1.2, BIAS2=1.2, VDD=0.99, VDDS=1.62, BUS_BIAS3=0, BUS_VSSS=0,
|   ESD_BIASFET=0, VSS=0
| Max Voltages:
|   BIAS1=1.2, BIAS2=1.2, VDD=1.21, VDDS=1.98, BUS_BIAS3=0, BUS_VSSS=0,
|   ESD_BIASFET=0, VSS=0
[Pulldown]
|   voltage   I(typ)   I(min)   I(max)
-1.8V     -6.003A    -6.315A    -5.869A
-1.091V   -280.7mA   -504mA     -250.8mA
-1.036V   -200.5mA   -290.7mA   -218mA
-981.8mV  -175.2mA   -175.2mA   -201.6mA
-872.7mV  -160.1mA   -111.6mA   -185.2mA
0V        -55.76mA   -39.03mA   -75.81mA
600mV     -7.855mA   -6.952mA   -12.38mA
1.964V    35.49mA    30.11mA    39.74mA
2.455V    78.52mA    60.74mA    110.7mA
3.109V    212.4mA    185.8mA    263.2mA
3.327V    277mA      258.1mA    381.5mA
3.6V      375.7mA    801mA      554.3mA
[Pullup]
|   voltage   I(typ)   I(min)   I(max)
-1.8V     319.4mA    317.6mA    593.1mA
-1.255V   179.7mA    111.7mA    296mA
-218.2mV  26.93mA    14.84mA    65.86mA
2.509V    -165.5mA   -146.2mA   -184.2mA
2.673V    -182.2mA   -368.2mA   -208.7mA
2.782V    -203.2mA   -924.5mA   -222.5mA
2.836V    -230.2mA   -1.302A    -228.1mA
2.945V    -496.6mA   -2.158A    -248.5mA
3.055V    -1.186A    -3.088A    -290mA
3.164V    -2.07A     -4.052A    -542.3mA
3.273V    -3.029A    -5.017A    -1.278A
3.6V      -6.007A    -7.911A    -4.201A
[Ramp]
| variable   typ   min   max
dV/dt_f 0.22191941/0.10502543n 0.18544881/0.16380958n 0.26187238/76.031105p
dV/dt_r 0.27568302/97.836825p 0.21779323/0.14894808n 0.32773538/70.135781p
R_load = 50
[Rising Waveform]
R_fixture = 50
V_fixture = 1.2V
V_fixture_min = 1.2V
V_fixture_max = 1.2V
|   time   V(typ)   V(min)   V(max)
0s        1.013V     1.034V     990.9mV
44.16ps   1.017V     1.034V     1.013V
77.91ps   1.051V     1.048V     1.151V
120.5ps   1.163V     1.088V     1.343V
141.3ps   1.228V     1.116V     1.387V
170ps     1.3V       1.162V     1.413V
205.9ps   1.347V     1.219V     1.422V
259.9ps   1.373V     1.282V     1.425V
361.8ps   1.385V     1.33V      1.424V
1ns       1.388V     1.35V      1.424V
[Falling Waveform]
R_fixture = 50
V_fixture = 1.2V
V_fixture_min = 1.2V
V_fixture_max = 1.2V
|   time   V(typ)   V(min)   V(max)
0s        1.387V     1.349V     1.423V
33.98ps   1.393V     1.35V      1.404V
72.35ps   1.363V     1.351V     1.239V
95.94ps   1.311V     1.343V     1.134V
119.3ps   1.243V     1.325V     1.063V
174.6ps   1.104V     1.254V     999.8mV
253.7ps   1.026V     1.143V     990mV
322.7ps   1.012V     1.081V     990.1mV
390.4ps   1.01V      1.051V     990.3mV
1ns       1.012V     1.033V     990.2mV
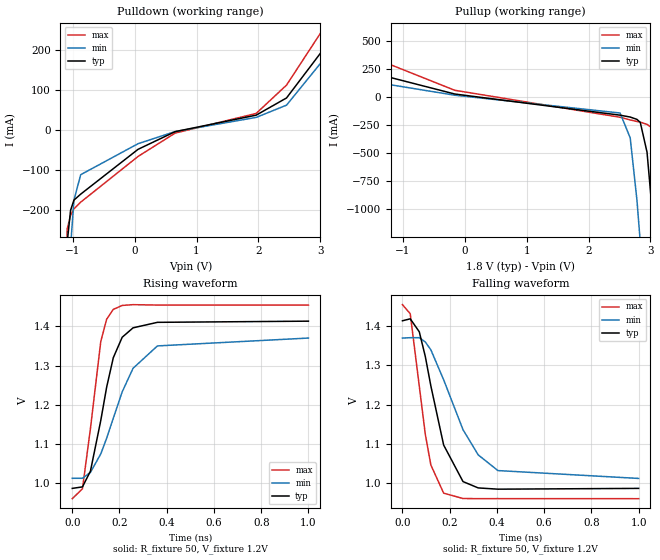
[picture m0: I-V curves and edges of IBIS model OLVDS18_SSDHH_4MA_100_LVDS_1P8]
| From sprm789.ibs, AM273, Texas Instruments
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|   Model Cell OLVDS18_SSDHH_4MA_100_LVDS_1P8
|OLVDS18_SSDHH_4MA_100_LVDS_1P8
[Model]   OLVDS18_SSDHH_4MA_100_LVDS_1P8
Model_type   Output
Polarity   Non-Inverting
Cref =  15.0001pF
Rref =  101.0000M
Vref =  0V
Vmeas =  1.08
C_comp   1.5p   1.5p   1.5p
[Temperature Range]   25   125   -40
[Voltage Range]   1.8   1.62   1.98
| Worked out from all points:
|   slope of the pulldown table from 0 to 0.27 V, typ, clamps not added: 9.42 ohm
|   slope of the pullup table from 0 to 0.27 V, typ, clamps not added: 21.5 ohm
|   rising waveform, R_fixture 50, V_fixture 1.2V: 20-80 % time 83.8ps typ, 136ps min, 56.5ps max; typ from 0.987 V to 1.41 V
|   falling waveform, R_fixture 50, V_fixture 1.2V: 20-80 % time 93ps typ, 154ps min, 64.2ps max; typ from 1.41 V to 0.987 V
| Nom Voltages:
|   BIAS1=1.2, BIAS2=1.2, VDD=1.1, VDDS=1.8, BUS_BIAS3=0, BUS_VSSS=0,
|   ESD_BIASFET=0, VSS=0
| Min Voltages:
|   BIAS1=1.2, BIAS2=1.2, VDD=0.99, VDDS=1.62, BUS_BIAS3=0, BUS_VSSS=0,
|   ESD_BIASFET=0, VSS=0
| Max Voltages:
|   BIAS1=1.2, BIAS2=1.2, VDD=1.21, VDDS=1.98, BUS_BIAS3=0, BUS_VSSS=0,
|   ESD_BIASFET=0, VSS=0
[Pulldown]
|   voltage   I(typ)   I(min)   I(max)
-1.8V     -6.003A    -6.315A    -5.869A
-1.091V   -280.7mA   -504.1mA   -246.9mA
-1.036V   -200.6mA   -290.9mA   -213.6mA
-981.8mV  -175.3mA   -175.4mA   -196.9mA
-872.7mV  -160.4mA   -111.9mA   -180.4mA
54.55mV   -48.61mA   -34.56mA   -66.4mA
654.5mV   -4.494mA   -4.259mA   -8.089mA
1.964V    36.6mA     30.99mA    40.87mA
2.455V    79.57mA    61.6mA     111.6mA
3.109V    212.7mA    185.8mA    266mA
3.327V    277.8mA    258.2mA    391mA
3.6V      376.4mA    800.9mA    572.2mA
[Pullup]
|   voltage   I(typ)   I(min)   I(max)
-1.8V     317.1mA    316.1mA    608.9mA
-1.255V   178.5mA    111.1mA    297.3mA
-163.6mV  23.71mA    12.92mA    57mA
2.509V    -165.4mA   -146mA     -184.1mA
2.673V    -182.1mA   -368.2mA   -208mA
2.782V    -203.1mA   -924.5mA   -221.8mA
2.836V    -230.1mA   -1.302A    -227.4mA
2.945V    -496.5mA   -2.158A    -247.8mA
3.055V    -1.186A    -3.088A    -289.3mA
3.164V    -2.07A     -4.052A    -541.9mA
3.273V    -3.029A    -5.017A    -1.278A
3.6V      -6.007A    -7.911A    -4.201A
[Ramp]
| variable   typ   min   max
dV/dt_f 0.25198894/0.10863952n 0.21079827/0.16888304n  0.2964766/78.18652p
dV/dt_r 0.30598585/94.613212p 0.24157281/0.14263972n 0.36561678/68.795913p
R_load = 50
[Rising Waveform]
R_fixture = 50
V_fixture = 1.2V
V_fixture_min = 1.2V
V_fixture_max = 1.2V
|   time   V(typ)   V(min)   V(max)
0s        987.3mV    1.013V     961.1mV
43.14ps   991.1mV    1.013V     986.3mV
76.87ps   1.031V     1.028V     1.139V
120.7ps   1.16V      1.075V     1.361V
145.6ps   1.245V     1.115V     1.418V
173.8ps   1.32V      1.166V     1.443V
211.4ps   1.372V     1.233V     1.453V
257.4ps   1.396V     1.293V     1.455V
360.6ps   1.41V      1.35V      1.454V
1ns       1.413V     1.37V      1.454V
[Falling Waveform]
R_fixture = 50
V_fixture = 1.2V
V_fixture_min = 1.2V
V_fixture_max = 1.2V
|   time   V(typ)   V(min)   V(max)
0s        1.413V     1.369V     1.454V
32.94ps   1.418V     1.37V      1.431V
71.31ps   1.385V     1.37V      1.247V
96.84ps   1.322V     1.359V     1.124V
120.4ps   1.247V     1.339V     1.046V
174.4ps   1.097V     1.263V     974.6mV
256.4ps   1.004V     1.136V     960.9mV
320.6ps   987.9mV    1.072V     960.6mV
404.2ps   984.7mV    1.032V     960.7mV
1ns       986.7mV    1.012V     960.5mV
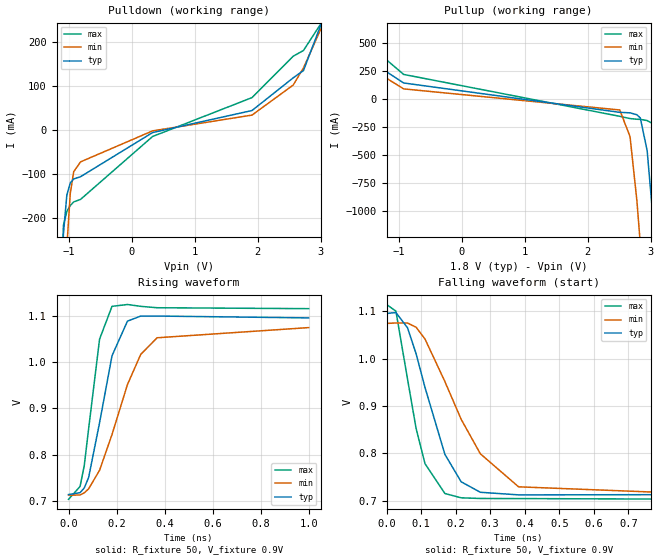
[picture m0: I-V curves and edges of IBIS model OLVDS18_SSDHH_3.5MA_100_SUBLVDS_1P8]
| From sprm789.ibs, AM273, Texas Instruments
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|   Model Cell OLVDS18_SSDHH_3.5MA_100_SUBLVDS_1P8
|OLVDS18_SSDHH_3.5MA_100_SUBLVDS_1P8
[Model]   OLVDS18_SSDHH_3.5MA_100_SUBLVDS_1P8
Model_type   Output
Polarity   Non-Inverting
Cref =  15.0001pF
Rref =  101.0000M
Vref =  0V
Vmeas =  1.08
C_comp   1.5p   1.5p   1.5p
[Temperature Range]   25   125   -40
[Voltage Range]   1.8   1.62   1.98
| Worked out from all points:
|   slope of the pulldown table from 0 to 0.27 V, typ, clamps not added: 15 ohm
|   slope of the pullup table from 0 to 0.27 V, typ, clamps not added: 11.6 ohm
|   rising waveform, R_fixture 50, V_fixture 0.9V: 20-80 % time 81.3ps typ, 142ps min, 55.5ps max; typ from 0.714 V to 1.1 V
|   falling waveform, R_fixture 50, V_fixture 0.9V: 20-80 % time 91.4ps typ, 147ps min, 63.3ps max; typ from 1.09 V to 0.713 V
| Nom Voltages:
|   BIAS1=1.2, BIAS2=1.2, VDD=1.1, VDDS=1.8, BUS_BIAS3=0, BUS_VSSS=0,
|   ESD_BIASFET=0, VSS=0
| Min Voltages:
|   BIAS1=1.2, BIAS2=1.2, VDD=0.99, VDDS=1.62, BUS_BIAS3=0, BUS_VSSS=0,
|   ESD_BIASFET=0, VSS=0
| Max Voltages:
|   BIAS1=1.2, BIAS2=1.2, VDD=1.21, VDDS=1.98, BUS_BIAS3=0, BUS_VSSS=0,
|   ESD_BIASFET=0, VSS=0
[Pulldown]
|   voltage   I(typ)   I(min)   I(max)
-1.8V     -5.998A    -6.311A    -5.865A
-1.091V   -237.5mA   -486.2mA   -217.5mA
-1.036V   -148.5mA   -266.6mA   -186mA
-981.8mV  -121.2mA   -145.5mA   -172.3mA
-927.3mV  -111.9mA   -95.49mA   -164.1mA
-818.2mV  -106.8mA   -73.06mA   -158.4mA
327.3mV   -6.43mA    -2.598mA   -15.38mA
1.909V    43.7mA     33.3mA     73.06mA
2.564V    118mA      101.6mA    167.2mA
2.727V    134.5mA    140.5mA    180.2mA
3.055V    257.4mA    245.7mA    252.3mA
3.6V      532.9mA    855.4mA    591.3mA
[Pullup]
|   voltage   I(typ)   I(min)   I(max)
-1.8V     459.9mA    390.8mA    630.7mA
-927.3mV  140.9mA    88.32mA    216.9mA
2.509V    -120.2mA   -99.03mA   -155.5mA
2.673V    -124.7mA   -337mA     -175.6mA
2.782V    -141.6mA   -908.1mA   -181.6mA
2.836V    -170.4mA   -1.29A     -182.7mA
2.945V    -461.4mA   -2.15A     -193.3mA
3.055V    -1.17A     -3.083A    -227.6mA
3.109V    -1.602A    -3.564A    -299.3mA
3.164V    -2.06A     -4.046A    -505.5mA
3.273V    -3.022A    -5.011A    -1.263A
3.6V      -6.001A    -7.906A    -4.195A
[Ramp]
| variable   typ   min   max
dV/dt_f 0.15341942/95.870667p 0.13018078/0.14447793n 0.19131894/84.726842p
dV/dt_r 0.21820451/83.902158p 0.18924918/0.13791391n 0.25341015/58.887344p
R_load = 50
[Rising Waveform]
R_fixture = 50
V_fixture = 0.9V
V_fixture_min = 0.9V
V_fixture_max = 0.9V
|   time   V(typ)   V(min)   V(max)
0s        713.6mV    712.3mV    703.3mV
48.17ps   717.8mV    712.7mV    731.3mV
65.54ps   727.9mV    717.4mV    776.5mV
83.62ps   750.5mV    726mV      855.8mV
129.3ps   869.2mV    766.2mV    1.05V
181.1ps   1.014V     843.6mV    1.121V
245.4ps   1.089V     951.7mV    1.125V
300.7ps   1.1V       1.017V     1.121V
369ps     1.1V       1.053V     1.118V
1ns       1.096V     1.075V     1.116V
[Falling Waveform]
R_fixture = 50
V_fixture = 0.9V
V_fixture_min = 0.9V
V_fixture_max = 0.9V
|   time   V(typ)   V(min)   V(max)
0s        1.095V     1.074V     1.114V
27.13ps   1.097V     1.075V     1.1V
60.63ps   1.065V     1.075V     957.2mV
85.56ps   1.01V      1.066V     852.4mV
111.4ps   938.7mV    1.041V     777.8mV
168.9ps   797.6mV    951.3mV    715mV
216ps     739.7mV    871.6mV    705.9mV
271.5ps   717.6mV    798.8mV    704.5mV
382.1ps   712.1mV    729.1mV    704.3mV
1ns       712.8mV    711.5mV    702.7mV
